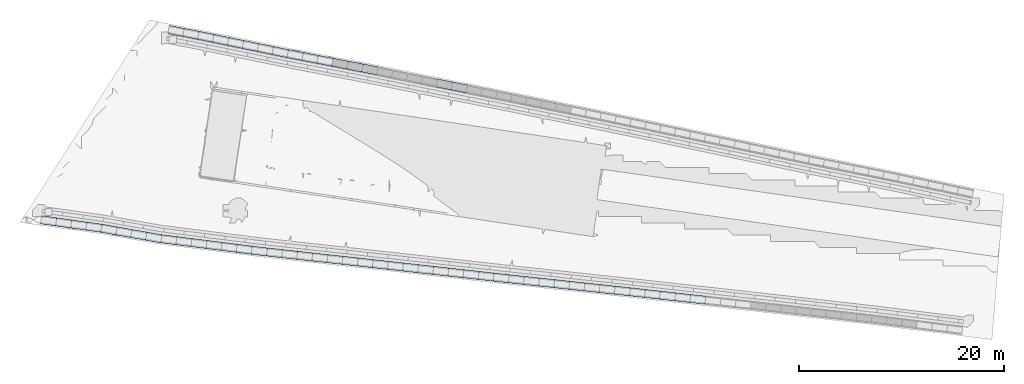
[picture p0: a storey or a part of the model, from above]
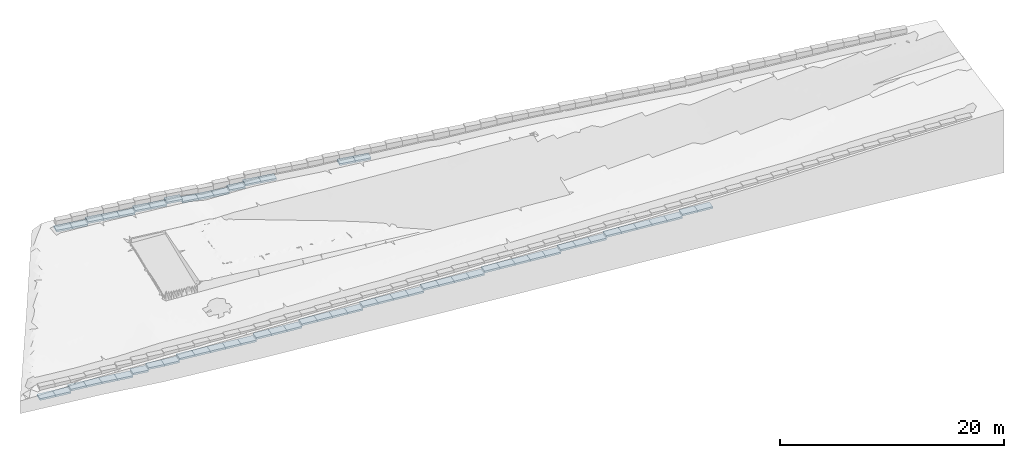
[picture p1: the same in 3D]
Properties of the parts of a building model (IFC4), part 1 of 3

# File
Description: ViewDefinition [CoordinationView]
File name: Casa_Sobreposta_Implantada.ifc
Time: 2026-10-02T10:00:33
Written by: IfcOpenShell 0.8.0
Made in: IfcOpenShell 0.8.0

# IfcProject, Casa Sobreposta · Lares · R05
Pset_CasaModel - Design: Casa Sobreposta; snapshot of current local configurator; ReferenceFile: 260617_CasaDFL_Estrutura_Terreno.ifc; ModelStatus: DESIGN_STUDY; North: Survey grid +Y; UpperFinishedFloor_m: 3.24; UpperDimensions: 32.00 x 7.90 m; Ramp: REMOVED R05; greenhouse via two existing internal stairs; EngineeringStatus: Member sizes, foundations, connections, bracing and environmental performance not verified; GroundFFL_m: 13.9; AreaLimit_m2: 250; CountedGeometricArea_m2: 248.622; GreenhouseExcludedByUser: yes

# IfcSite, Lares · Rua das Mercês · artigo 4771
Pset_SurveySource - File: GN_09.26_213 Lares.dwg; SHA256: 0bca0a0751148bad1398f92d81b795428f94a57fea5e37dec0e125cea70402a1; Area_m2: 1636.5; BoundaryHandle: 31B; CoordinateReference: PT-TM06 / ETRS89; TerrainStatus: Proposed grading; original survey in separate IFC

# IfcBuilding, Casa Sobreposta
Pset_CasaFloorAssembly - UpperFFL_m: 3.24; JoistUnderside_m: 2.968; JoistDepth_m: 0.24; OSB_m: 0.02; Membrane_m: 0.002; ProtectiveFinish_m: 0.01; Basis: TJI240 + OSB20 from reference; greenhouse waterproofing/finish assumed; imposed loads unverified
Pset_CasaPlacement - GroundFloorSurveyLevel_m: 13.9; GreenhouseSurveyLevel_m: 17.14; RotationFromGridEast_deg: -8.5; BoundarySetbackRequired_m: 3; RuleBasis: User project constraint

# IfcBuildingStorey (3)
In: Casa Sobreposta
Name | Elevation (m)
00 · Habitação e estacionamento | 13.9
01 · Jardim de inverno | 17.14
-01 · Cisterna sob o terraço | 11.3

# IfcSpace (18)
Pset_CasaProvenance - DesignSource: Casa Sobreposta / configuration.json; ReferenceFile: 260617_CasaDFL_Estrutura_Terreno.ifc; ConstructionBasis: DESIGN_ASSUMPTION; Note: Functional zone from configurator; overlaps with partition footprints removed on ground floor. Not certified usable floor area.
Name | In | PredefinedType | NetFloorArea (m2)
Sala | 00 · Habitação e estacionamento | INTERNAL | 31.359
Cozinha | 00 · Habitação e estacionamento | INTERNAL | 9.94248
Banho | 00 · Habitação e estacionamento | INTERNAL | 7.19804
WC | 00 · Habitação e estacionamento | INTERNAL | 1.231
Serviço | 00 · Habitação e estacionamento | INTERNAL | 4.16058
Acesso IS | 00 · Habitação e estacionamento | INTERNAL | 3.99017
Quarto 1 | 00 · Habitação e estacionamento | INTERNAL | 13.1145
Quarto 2 | 00 · Habitação e estacionamento | INTERNAL | 13.1145
Quarto / escritório | 00 · Habitação e estacionamento | INTERNAL | 37.8909
Circulação | 00 · Habitação e estacionamento | INTERNAL | 18.1139
Estacionamento · 2 lugares | 00 · Habitação e estacionamento | EXTERNAL | 32.55
Galeria sul · balanço 1,50 m | 01 · Jardim de inverno | INTERNAL | 48
Jardim de inverno | 01 · Jardim de inverno | INTERNAL | 47.852
Circulação / estar | 01 · Jardim de inverno | INTERNAL | 68.8278
Banho superior | 01 · Jardim de inverno | INTERNAL | 7.3678
Cultivo / jardim | 01 · Jardim de inverno | INTERNAL | 25.5734
Estar sobre a garagem | 01 · Jardim de inverno | INTERNAL | 21.292
Balanço | 01 · Jardim de inverno | INTERNAL | 25.6

# IfcAirToAirHeatRecovery, VMC com recuperação · esquema
In: 00 · Habitação e estacionamento
PredefinedType: FIXEDPLATECOUNTERFLOWEXCHANGER; Material: Aço galvanizado / Stahl verzinkt
Pset_CasaProvenance - DesignSource: Casa Sobreposta / configuration.json; ReferenceFile: 260617_CasaDFL_Estrutura_Terreno.ifc; ConstructionBasis: DESIGN_ASSUMPTION

# IfcAnnotation (4)
Pset_CasaProvenance - DesignSource: Casa Sobreposta / configuration.json; ReferenceFile: 260617_CasaDFL_Estrutura_Terreno.ifc; ConstructionBasis: DESIGN_ASSUMPTION
Name | In
Lugar P1 · 2.50 x 5.00 m | 00 · Habitação e estacionamento
Lugar P2 · 2.50 x 5.00 m | 00 · Habitação e estacionamento
Limite levantado · 31B | Lares · Rua das Mercês · artigo 4771
Afastamento de implantação · 3 m | Lares · Rua das Mercês · artigo 4771

# IfcBeam (104)
In: 01 · Jardim de inverno
Material: Madeira / Bauholz (2), OSB
Pset_CasaProvenance - DesignSource: Casa Sobreposta / configuration.json; ReferenceFile: 260617_CasaDFL_Estrutura_Terreno.ifc; ConstructionBasis: ADAPTED_REFERENCE; Note: Composite wood flanges + OSB web; 600 mm study spacing. Reference 44.45 mm width / 9.525 mm web; flanges regularised to 28 mm. Not structurally sized.
Name
TJI240 · 0.065 / -1.15
TJI240 · 4.065 / -1.15
TJI240 · 8.065 / -1.15
TJI240 · 12.065 / -1.15
TJI240 · 16.065 / -1.15
TJI240 · 20.065 / -1.15
TJI240 · 24.065 / -1.15
TJI240 · 28.065 / -1.15
TJI240 · 0.065 / -0.55
TJI240 · 4.065 / -0.55
TJI240 · 8.065 / -0.55
TJI240 · 12.065 / -0.55
TJI240 · 16.065 / -0.55
TJI240 · 20.065 / -0.55
TJI240 · 24.065 / -0.55
TJI240 · 28.065 / -0.55
TJI240 · 0.065 / 0.05
TJI240 · 4.065 / 0.05
TJI240 · 8.065 / 0.05
TJI240 · 12.065 / 0.05
TJI240 · 16.065 / 0.05
TJI240 · 20.065 / 0.05
TJI240 · 24.065 / 0.05
TJI240 · 28.065 / 0.05
TJI240 · 0.065 / 0.65
TJI240 · 4.065 / 0.65
TJI240 · 8.065 / 0.65
TJI240 · 12.065 / 0.65
TJI240 · 16.065 / 0.65
TJI240 · 20.065 / 0.65
TJI240 · 24.065 / 0.65
TJI240 · 28.065 / 0.65
TJI240 · 0.970 / 1.25
TJI240 · 4.065 / 1.25
TJI240 · 8.065 / 1.25
TJI240 · 12.065 / 1.25
TJI240 · 16.065 / 1.25
TJI240 · 20.065 / 1.25
TJI240 · 25.040 / 1.25
TJI240 · 28.065 / 1.25
TJI240 · 0.970 / 1.85
TJI240 · 4.065 / 1.85
TJI240 · 8.065 / 1.85
TJI240 · 12.065 / 1.85
TJI240 · 16.065 / 1.85
TJI240 · 20.065 / 1.85
TJI240 · 25.040 / 1.85
TJI240 · 28.065 / 1.85
TJI240 · 0.970 / 2.45
TJI240 · 4.065 / 2.45
TJI240 · 8.065 / 2.45
TJI240 · 12.065 / 2.45
TJI240 · 16.065 / 2.45
TJI240 · 20.065 / 2.45
TJI240 · 25.040 / 2.45
TJI240 · 28.065 / 2.45
TJI240 · 0.970 / 3.05
TJI240 · 4.065 / 3.05
TJI240 · 8.065 / 3.05
TJI240 · 12.065 / 3.05
TJI240 · 16.065 / 3.05
TJI240 · 20.065 / 3.05
TJI240 · 25.040 / 3.05
TJI240 · 28.065 / 3.05
TJI240 · 0.970 / 3.65
TJI240 · 4.065 / 3.65
TJI240 · 8.065 / 3.65
TJI240 · 12.065 / 3.65
TJI240 · 16.065 / 3.65
TJI240 · 20.065 / 3.65
TJI240 · 25.040 / 3.65
TJI240 · 28.065 / 3.65
TJI240 · 0.970 / 4.25
TJI240 · 4.065 / 4.25
TJI240 · 8.065 / 4.25
TJI240 · 12.065 / 4.25
TJI240 · 16.065 / 4.25
TJI240 · 20.065 / 4.25
TJI240 · 25.040 / 4.25
TJI240 · 28.065 / 4.25
TJI240 · 0.970 / 4.85
TJI240 · 4.065 / 4.85
TJI240 · 8.065 / 4.85
TJI240 · 12.065 / 4.85
TJI240 · 16.065 / 4.85
TJI240 · 20.065 / 4.85
TJI240 · 25.040 / 4.85
TJI240 · 28.065 / 4.85
TJI240 · 0.970 / 5.45
TJI240 · 4.065 / 5.45
TJI240 · 8.065 / 5.45
TJI240 · 12.065 / 5.45
TJI240 · 16.065 / 5.45
TJI240 · 20.065 / 5.45
TJI240 · 25.040 / 5.45
TJI240 · 28.065 / 5.45
TJI240 · 0.065 / 6.05
TJI240 · 4.065 / 6.05
TJI240 · 8.065 / 6.05
TJI240 · 12.065 / 6.05
TJI240 · 16.065 / 6.05
TJI240 · 20.065 / 6.05
TJI240 · 24.065 / 6.05
TJI240 · 28.065 / 6.05

# IfcBeam: IPE240 / steel (46)
Type - Material: Aço pintado / Stahl lackiert
Pset_CasaProvenance - DesignSource: Casa Sobreposta / configuration.json; ReferenceFile: 260617_CasaDFL_Estrutura_Terreno.ifc; ConstructionBasis: ADAPTED_REFERENCE; Note: Reference section; spans, stability and connections require design.
Name | In
Viga longitudinal 0 / 0.12 | 01 · Jardim de inverno
Viga longitudinal 4 / 0.12 | 01 · Jardim de inverno
Viga longitudinal 8 / 0.12 | 01 · Jardim de inverno
Viga longitudinal 12 / 0.12 | 01 · Jardim de inverno
Viga longitudinal 16 / 0.12 | 01 · Jardim de inverno
Viga longitudinal 20 / 0.12 | 01 · Jardim de inverno
Viga longitudinal 24 / 0.12 | 01 · Jardim de inverno
Viga longitudinal 28 / 0.12 | 01 · Jardim de inverno
Viga longitudinal 0 / 6.28 | 01 · Jardim de inverno
Viga longitudinal 4 / 6.28 | 01 · Jardim de inverno
Viga longitudinal 8 / 6.28 | 01 · Jardim de inverno
Viga longitudinal 12 / 6.28 | 01 · Jardim de inverno
Viga longitudinal 16 / 6.28 | 01 · Jardim de inverno
Viga longitudinal 20 / 6.28 | 01 · Jardim de inverno
Viga longitudinal 24 / 6.28 | 01 · Jardim de inverno
Viga longitudinal 28 / 6.28 | 01 · Jardim de inverno
Viga longitudinal 0 / -1.44 | 01 · Jardim de inverno
Viga longitudinal 4 / -1.44 | 01 · Jardim de inverno
Viga longitudinal 8 / -1.44 | 01 · Jardim de inverno
Viga longitudinal 12 / -1.44 | 01 · Jardim de inverno
Viga longitudinal 16 / -1.44 | 01 · Jardim de inverno
Viga longitudinal 20 / -1.44 | 01 · Jardim de inverno
Viga longitudinal 24 / -1.44 | 01 · Jardim de inverno
Viga longitudinal 28 / -1.44 | 01 · Jardim de inverno
2 x Viga transversal eixo 0 | 01 · Jardim de inverno
Viga transversal eixo 4 | 01 · Jardim de inverno
Viga transversal eixo 8 | 01 · Jardim de inverno
Viga transversal eixo 12 | 01 · Jardim de inverno
Viga transversal eixo 16 | 01 · Jardim de inverno
Viga transversal eixo 20 | 01 · Jardim de inverno
Viga transversal eixo 24 | 01 · Jardim de inverno
Viga transversal eixo 28 | 01 · Jardim de inverno
Viga transversal eixo 32 | 01 · Jardim de inverno
2 x Longarina do vão 1 | 01 · Jardim de inverno
2 x Cabeceira do vão 1 | 01 · Jardim de inverno
2 x Longarina do vão 2 | 01 · Jardim de inverno
2 x Cabeceira do vão 2 | 01 · Jardim de inverno
2 x Varanda · viga de bordo | 00 · Habitação e estacionamento
2 x Varanda · viga transversal | 00 · Habitação e estacionamento

# IfcBeam: RHS100x60x4 / steel (4)
In: 00 · Habitação e estacionamento
Type - Material: Aço pintado / Stahl lackiert
Pset_CasaProvenance - DesignSource: Casa Sobreposta / configuration.json; ReferenceFile: 260617_CasaDFL_Estrutura_Terreno.ifc; ConstructionBasis: DESIGN_ASSUMPTION; Note: Reference section; spans, stability and connections require design.

# IfcBuildingElementProxy: Cisterna · água a 2,00 m, hipótese
In: -01 · Cisterna sob o terraço
PredefinedType: USERDEFINED; Material: Água pluvial · nível ilustrativo
Pset_CasaProvenance - DesignSource: Casa Sobreposta / configuration.json; ReferenceFile: 260617_CasaDFL_Estrutura_Terreno.ifc; ConstructionBasis: DESIGN_ASSUMPTION; Note: Illustrative water envelope, not concrete or a certified operating capacity.

# IfcBuildingElementProxy: DRAINAGE_COLLECTION_RESERVE (2)
In: Lares · Rua das Mercês · artigo 4771
PredefinedType: USERDEFINED; Material: Betão armado / Stahlbeton
Pset_CasaProvenance - DesignSource: Casa Sobreposta / configuration.json; ReferenceFile: 260617_CasaDFL_Estrutura_Terreno.ifc; ConstructionBasis: DESIGN_ASSUMPTION; Note: Collection/silt chamber spatial reserve; outlet and storage not designed. No discharge to neighbour is assumed.
Name
Limite north · reserva de caixa de recolha
Limite south · reserva de caixa de recolha

# IfcBuildingElementProxy: INTERCEPTOR_SWALE (87)
In: Lares · Rua das Mercês · artigo 4771
PredefinedType: USERDEFINED; Material: Brita drenante
Pset_CasaProvenance - DesignSource: Casa Sobreposta / configuration.json; ReferenceFile: 260617_CasaDFL_Estrutura_Terreno.ifc; ConstructionBasis: DESIGN_ASSUMPTION; Note: Gravel-bottom interception swale; 0.90 m overall terrain cut, nominal 0.18 m depth. Filter, gradients, capacity and permitted outlet require hydraulic design.
Name
Limite north · vala drenante 01
Limite north · vala drenante 02
Limite north · vala drenante 03
Limite north · vala drenante 04
Limite north · vala drenante 05
Limite north · vala drenante 06
Limite north · vala drenante 07
Limite north · vala drenante 08
Limite north · vala drenante 09
Limite north · vala drenante 10
Limite north · vala drenante 11
Limite north · vala drenante 12
Limite north · vala drenante 13
Limite north · vala drenante 14
Limite north · vala drenante 15
Limite north · vala drenante 16
Limite north · vala drenante 17
Limite north · vala drenante 18
Limite north · vala drenante 19
Limite north · vala drenante 20
Limite north · vala drenante 21
Limite north · vala drenante 22
Limite north · vala drenante 23
Limite north · vala drenante 24
Limite north · vala drenante 25
Limite north · vala drenante 26
Limite north · vala drenante 27
Limite north · vala drenante 28
Limite north · vala drenante 29
Limite north · vala drenante 30
Limite north · vala drenante 31
Limite north · vala drenante 32
Limite north · vala drenante 33
Limite north · vala drenante 34
Limite north · vala drenante 35
Limite north · vala drenante 36
Limite north · vala drenante 37
Limite north · vala drenante 38
Limite north · vala drenante 39
Limite north · vala drenante 40
Limite north · vala drenante 41
Limite south · vala drenante 01
Limite south · vala drenante 02
Limite south · vala drenante 03
Limite south · vala drenante 04
Limite south · vala drenante 05
Limite south · vala drenante 06
Limite south · vala drenante 07
Limite south · vala drenante 08
Limite south · vala drenante 09
Limite south · vala drenante 10
Limite south · vala drenante 11
Limite south · vala drenante 12
Limite south · vala drenante 13
Limite south · vala drenante 14
Limite south · vala drenante 15
Limite south · vala drenante 16
Limite south · vala drenante 17
Limite south · vala drenante 18
Limite south · vala drenante 19
Limite south · vala drenante 20
Limite south · vala drenante 21
Limite south · vala drenante 22
Limite south · vala drenante 23
Limite south · vala drenante 24
Limite south · vala drenante 25
Limite south · vala drenante 26
Limite south · vala drenante 27
Limite south · vala drenante 28
Limite south · vala drenante 29
Limite south · vala drenante 30
Limite south · vala drenante 31
Limite south · vala drenante 32
Limite south · vala drenante 33
Limite south · vala drenante 34
Limite south · vala drenante 35
Limite south · vala drenante 36
Limite south · vala drenante 37
Limite south · vala drenante 38
Limite south · vala drenante 39
Limite south · vala drenante 40
Limite south · vala drenante 41
Limite south · vala drenante 42
Limite south · vala drenante 43
Limite south · vala drenante 44
Limite south · vala drenante 45
Limite south · vala drenante 46

# IfcBuildingElementProxy: Trepadeiras · floreira (10)
In: 00 · Habitação e estacionamento
PredefinedType: USERDEFINED; Material: Betão armado / Stahlbeton
Pset_CasaProvenance - DesignSource: Casa Sobreposta / configuration.json; ReferenceFile: 260617_CasaDFL_Estrutura_Terreno.ifc; ConstructionBasis: DESIGN_ASSUMPTION; Note: Indicative planter; soil volume, irrigation, root space and waterproofing to design.

# IfcColumn (16)
In: 00 · Habitação e estacionamento
Material: Betão armado / Stahlbeton
Pset_CasaProvenance - DesignSource: Casa Sobreposta / configuration.json; ReferenceFile: 260617_CasaDFL_Estrutura_Terreno.ifc; ConstructionBasis: ADAPTED_REFERENCE
Name
Pedestal 1A · betão 400 x 400
Pedestal 1B · betão 400 x 400
Pedestal 2A · betão 400 x 400
Pedestal 2B · betão 400 x 400
Pedestal 3A · betão 400 x 400
Pedestal 3B · betão 400 x 400
Pedestal 4A · betão 400 x 400
Pedestal 4B · betão 400 x 400
Pedestal 5A · betão 400 x 400
Pedestal 5B · betão 400 x 400
Pedestal 6A · betão 400 x 400
Pedestal 6B · betão 400 x 400
Pedestal 7A · betão 400 x 400
Pedestal 7B · betão 400 x 400
Pedestal 8A · betão 400 x 400
Pedestal 8B · betão 400 x 400

# IfcColumn: IPE240 / steel (46)
Type - Material: Aço pintado / Stahl lackiert
Pset_CasaProvenance - DesignSource: Casa Sobreposta / configuration.json; ReferenceFile: 260617_CasaDFL_Estrutura_Terreno.ifc; ConstructionBasis: ADAPTED_REFERENCE; Note: Reference section; spans, stability and connections require design.
Name | In
Pilar 1A · IPE240 | 00 · Habitação e estacionamento
Pilar estufa 1A · IPE240 | 01 · Jardim de inverno
Pilar 1B · IPE240 | 00 · Habitação e estacionamento
Pilar estufa 1B · IPE240 | 01 · Jardim de inverno
Pilar 2A · IPE240 | 00 · Habitação e estacionamento
Pilar estufa 2A · IPE240 | 01 · Jardim de inverno
Pilar 2B · IPE240 | 00 · Habitação e estacionamento
Pilar estufa 2B · IPE240 | 01 · Jardim de inverno
Pilar 3A · IPE240 | 00 · Habitação e estacionamento
Pilar estufa 3A · IPE240 | 01 · Jardim de inverno
Pilar 3B · IPE240 | 00 · Habitação e estacionamento
Pilar estufa 3B · IPE240 | 01 · Jardim de inverno
Pilar 4A · IPE240 | 00 · Habitação e estacionamento
Pilar estufa 4A · IPE240 | 01 · Jardim de inverno
Pilar 4B · IPE240 | 00 · Habitação e estacionamento
Pilar estufa 4B · IPE240 | 01 · Jardim de inverno
Pilar 5A · IPE240 | 00 · Habitação e estacionamento
Pilar estufa 5A · IPE240 | 01 · Jardim de inverno
Pilar 5B · IPE240 | 00 · Habitação e estacionamento
Pilar estufa 5B · IPE240 | 01 · Jardim de inverno
Pilar 6A · IPE240 | 00 · Habitação e estacionamento
Pilar estufa 6A · IPE240 | 01 · Jardim de inverno
Pilar 6B · IPE240 | 00 · Habitação e estacionamento
Pilar estufa 6B · IPE240 | 01 · Jardim de inverno
Pilar 7A · IPE240 | 00 · Habitação e estacionamento
Pilar estufa 7A · IPE240 | 01 · Jardim de inverno
Pilar 7B · IPE240 | 00 · Habitação e estacionamento
Pilar estufa 7B · IPE240 | 01 · Jardim de inverno
Pilar 8A · IPE240 | 00 · Habitação e estacionamento
Pilar estufa 8A · IPE240 | 01 · Jardim de inverno
Pilar 8B · IPE240 | 00 · Habitação e estacionamento
Pilar estufa 8B · IPE240 | 01 · Jardim de inverno
4 x Pérgola · pilar de duplo pé-direito | 00 · Habitação e estacionamento
9 x Projeção estufa · pilar sul ao pódio | 00 · Habitação e estacionamento
Projeção estufa · pilar nascente norte | 00 · Habitação e estacionamento

# IfcColumn: RHS80x60x4 / steel (4)
In: 00 · Habitação e estacionamento
Type - Material: Aço pintado / Stahl lackiert
Pset_CasaProvenance - DesignSource: Casa Sobreposta / configuration.json; ReferenceFile: 260617_CasaDFL_Estrutura_Terreno.ifc; ConstructionBasis: DESIGN_ASSUMPTION; Note: Reference section; spans, stability and connections require design.

# IfcCovering (9)
Pset_CasaProvenance - DesignSource: Casa Sobreposta / configuration.json; ReferenceFile: 260617_CasaDFL_Estrutura_Terreno.ifc; ConstructionBasis: DESIGN_ASSUMPTION
Name | In | PredefinedType | Material
Impermeabilização da estufa · hipótese | 01 · Jardim de inverno | FLOORING | Membrana impermeável — hipótese | Pset_CasaProvenance - Note: Two real stair voids. Light protective finish assumed; drains and waterproof upstands require detailing.
Proteção do pavimento · hipótese | 01 · Jardim de inverno | FLOORING | Pavimento protetor leve — hipótese | Pset_CasaProvenance - Note: Two real stair voids. Light protective finish assumed; drains and waterproof upstands require detailing.
Teto caixa térmica 1 | 01 · Jardim de inverno | CEILING | Pavimento protetor leve — hipótese
Teto caixa térmica 2 | 01 · Jardim de inverno | CEILING | Pavimento protetor leve — hipótese
Cisterna · camada drenante 100 mm | -01 · Cisterna sob o terraço | FLOORING | Brita drenante
Cisterna · impermeabilização poente | -01 · Cisterna sob o terraço | MEMBRANE | Membrana impermeável — hipótese
Cisterna · impermeabilização norte | -01 · Cisterna sob o terraço | MEMBRANE | Membrana impermeável — hipótese
Cisterna · impermeabilização sul | -01 · Cisterna sob o terraço | MEMBRANE | Membrana impermeável — hipótese
Cisterna · impermeabilização nascente | -01 · Cisterna sob o terraço | MEMBRANE | Membrana impermeável — hipótese

# IfcCovering: Cortina interior · 75% (9)
In: 01 · Jardim de inverno
PredefinedType: USERDEFINED; Material: Tecido de sombreamento — hipótese
Pset_CasaProvenance - DesignSource: Casa Sobreposta / configuration.json; ReferenceFile: 260617_CasaDFL_Estrutura_Terreno.ifc; ConstructionBasis: DESIGN_ASSUMPTION; Note: 75% deployment snapshot; fabric specification and cables not sized.

# IfcCovering: Pátio · sombreador têxtil retrátil (2)
In: 00 · Habitação e estacionamento
PredefinedType: USERDEFINED; Material: Tecido de sombreamento — hipótese
Pset_CasaProvenance - DesignSource: Casa Sobreposta / configuration.json; ReferenceFile: 260617_CasaDFL_Estrutura_Terreno.ifc; ConstructionBasis: DESIGN_ASSUMPTION; Note: Same fabric intent as internal shades, shown partially deployed. No wind-speed rating; retraction does not prove storm safety.

# IfcDistributionSystem (7)
Name | PredefinedType
cold · traçados preliminares | DOMESTICCOLDWATER
hot · traçados preliminares | DOMESTICHOTWATER
waste · traçados preliminares | DRAINAGE
vent · traçados preliminares | VENT
supply · traçados preliminares | VENTILATION
extract · traçados preliminares | VENTILATION
ground · traçados preliminares | HEATING

# IfcDoor (22)
PredefinedType: DOOR
Pset_CasaProvenance - DesignSource: Casa Sobreposta / configuration.json; ReferenceFile: 260617_CasaDFL_Estrutura_Terreno.ifc
Name | In | OverallHeight (m) | OverallWidth (m) | OperationType | Material | ConstructionBasis
Porta interior 1 | 00 · Habitação e estacionamento | 2.1 | 0.830093 | SINGLE_SWING_LEFT | OSB | ADAPTED_REFERENCE
Porta interior 2 | 00 · Habitação e estacionamento | 2.1 | 0.830093 | SINGLE_SWING_LEFT | OSB | ADAPTED_REFERENCE
Porta interior 3 | 00 · Habitação e estacionamento | 2.1 | 0.730086 | SINGLE_SWING_LEFT | OSB | ADAPTED_REFERENCE
Porta interior 4 | 00 · Habitação e estacionamento | 2.1 | 0.830092 | SINGLE_SWING_LEFT | OSB | ADAPTED_REFERENCE
Porta interior 5 | 00 · Habitação e estacionamento | 2.1 | 0.830077 | SINGLE_SWING_LEFT | OSB | ADAPTED_REFERENCE
Porta interior 6 | 00 · Habitação e estacionamento | 2.1 | 0.730017 | SINGLE_SWING_LEFT | OSB | ADAPTED_REFERENCE
Porta do estacionamento | 00 · Habitação e estacionamento | 2.1 | 0.83 | SINGLE_SWING_LEFT | Aço pintado / Stahl lackiert | ADAPTED_REFERENCE
Folha de correr sul 2 | 00 · Habitação e estacionamento | 2.918 | 1.97133 | SLIDING_TO_LEFT | Vidro / Normalglas | DESIGN_ASSUMPTION
Folha de correr sul 4 | 00 · Habitação e estacionamento | 2.918 | 1.97133 | SLIDING_TO_LEFT | Vidro / Normalglas | DESIGN_ASSUMPTION
Folha de correr sul 6 | 00 · Habitação e estacionamento | 2.918 | 1.97133 | SLIDING_TO_LEFT | Vidro / Normalglas | DESIGN_ASSUMPTION
Folha de correr sul 8 | 00 · Habitação e estacionamento | 2.918 | 1.97133 | SLIDING_TO_LEFT | Vidro / Normalglas | DESIGN_ASSUMPTION
Folha de correr sul 10 | 00 · Habitação e estacionamento | 2.918 | 1.97133 | SLIDING_TO_LEFT | Vidro / Normalglas | DESIGN_ASSUMPTION
Folha de correr sul 12 | 00 · Habitação e estacionamento | 2.918 | 0.614 | SLIDING_TO_LEFT | Vidro / Normalglas | DESIGN_ASSUMPTION
Fachada poente integralmente envidraçada · módulo 4 | 00 · Habitação e estacionamento | 2.918 | 1.55 | SLIDING_TO_LEFT | Vidro / Normalglas | DESIGN_ASSUMPTION | Pset_CasaGlazedFacade - Revision: R02 · kiwi pergola; Facade: WEST / highlighted end in user sketch; Infill: Full-height glazing; no opaque infill; GlazingSpecification: 8 mm nominal representation only; insulated safety glazing assembly to specify
Porta banho superior | 01 · Jardim de inverno | 2.1 | 0.8 | SINGLE_SWING_LEFT | OSB | ADAPTED_REFERENCE
Varanda · porta de correr oeste | 01 · Jardim de inverno | 2.15 | 1.05 | SLIDING_TO_LEFT | Vidro / Normalglas | DESIGN_ASSUMPTION
Caixa térmica 1 · north | 01 · Jardim de inverno | 2.15 | 0.9 | SLIDING_TO_LEFT | Vidro / Normalglas | DESIGN_ASSUMPTION
Caixa térmica 2 · south | 01 · Jardim de inverno | 2.15 | 0.91 | SLIDING_TO_LEFT | Vidro / Normalglas | DESIGN_ASSUMPTION
2 x Contentor · porta dupla | 00 · Habitação e estacionamento | 2.39 | 1.17 | SINGLE_SWING_LEFT | Contentor · pintura 1 | DESIGN_ASSUMPTION
2 x Contentor · porta dupla | 00 · Habitação e estacionamento | 2.39 | 1.17 | SINGLE_SWING_LEFT | Contentor · pintura 2 | DESIGN_ASSUMPTION

# IfcDuctSegment: D0.09 / extract (8)
In: 00 · Habitação e estacionamento
Type - Material: extract · traçado de estudo
Pset_CasaProvenance - DesignSource: Casa Sobreposta / configuration.json; ReferenceFile: 260617_CasaDFL_Estrutura_Terreno.ifc; ConstructionBasis: DESIGN_ASSUMPTION; Note: Route only. Display diameter is not a specified pipe/duct size; fittings, ports, insulation and sizing not developed.
Group: extract · traçados preliminares

# IfcDuctSegment: D0.09 / supply (11)
In: 00 · Habitação e estacionamento
Type - Material: supply · traçado de estudo
Pset_CasaProvenance - DesignSource: Casa Sobreposta / configuration.json; ReferenceFile: 260617_CasaDFL_Estrutura_Terreno.ifc; ConstructionBasis: DESIGN_ASSUMPTION; Note: Route only. Display diameter is not a specified pipe/duct size; fittings, ports, insulation and sizing not developed.
Group: supply · traçados preliminares

# IfcElementAssembly: CISTERN_PODIUM, Pódio · projeção da estufa e cisterna
In: 00 · Habitação e estacionamento
PredefinedType: USERDEFINED
Pset_CasaProvenance - DesignSource: Casa Sobreposta / configuration.json; ReferenceFile: 260617_CasaDFL_Estrutura_Terreno.ifc; ConstructionBasis: DESIGN_ASSUMPTION
Pset_CasaPodium - TankGrossPlan_m2: 23; TankBaseLevel_m: 11.3; MinimumInternalHeight_m: 2.31; FloorSupport: Suspended west terrace; east platform on engineered fill; PlanningAssumption: 23 m2 still reserved conservatively in counted schedule; no tank exemption asserted

# IfcElementAssembly: EXISTING_SHIPPING_CONTAINER (2)
In: 00 · Habitação e estacionamento
PredefinedType: USERDEFINED
Pset_CasaProvenance - DesignSource: Casa Sobreposta / configuration.json; ReferenceFile: 260617_CasaDFL_Estrutura_Terreno.ifc; ConstructionBasis: DESIGN_ASSUMPTION
Pset_CasaExistingContext - Length_m: 6; WidthAssumed_m: 2.44; HeightAssumed_m: 2.59; Location: Approximate from user plan markup, not surveyed; Status: Existing context; not included in new building setback or new floor-area schedule; Colour: Illustrative, condition not surveyed
Name
Contentor existente 1 · 6 m
Contentor existente 2 · 6 m

# IfcElementAssembly: LIVING_SHADE_TRELLIS, Fachada sul e pátio · estrutura e trepadeiras
In: 00 · Habitação e estacionamento
PredefinedType: USERDEFINED
Pset_CasaProvenance - DesignSource: Casa Sobreposta / configuration.json; ReferenceFile: 260617_CasaDFL_Estrutura_Terreno.ifc; ConstructionBasis: DESIGN_ASSUMPTION

# IfcElementAssembly: PERGOLA_GREENHOUSE_EXTENSION, Pérgola · prolongamento da estufa 6 m
In: 00 · Habitação e estacionamento
PredefinedType: USERDEFINED
Pset_CasaProvenance - DesignSource: Casa Sobreposta / configuration.json; ReferenceFile: 260617_CasaDFL_Estrutura_Terreno.ifc; ConstructionBasis: DESIGN_ASSUMPTION
Pset_CasaVeranda - ClearWidth_m: 1.2; GrossArea_m2: 9.875; PlanningStatus: Counted conservatively in 250 m2 budget; municipal classification unconfirmed
Pset_CasaPergola - Projection_m: 6; Frontage_m: 7.9; OpenCanopyArea_m2: 47.4; EavesRelativeHeight_m: 6.22; Roof: Open extension of greenhouse curved profile, no glass enclosure; StructuralStatus: Gravity and lateral load path indicated; no wind-speed rating or member/anchor verification

# IfcFooting (179)
Material: Betão armado / Stahlbeton
Pset_CasaProvenance - DesignSource: Casa Sobreposta / configuration.json; ReferenceFile: 260617_CasaDFL_Estrutura_Terreno.ifc
Name | In | PredefinedType | ConstructionBasis | Note
Sapata 1A · hipótese | 00 · Habitação e estacionamento | PAD_FOOTING | ADAPTED_REFERENCE | 1.20 x 1.20 x 0.35 m assumed pad; R03 steps below original ground where survey is available. Bearing, settlement and reinforcement unverified.
Sapata 1B · hipótese | 00 · Habitação e estacionamento | PAD_FOOTING | ADAPTED_REFERENCE | 1.20 x 1.20 x 0.35 m assumed pad; R03 steps below original ground where survey is available. Bearing, settlement and reinforcement unverified.
Sapata 2A · hipótese | 00 · Habitação e estacionamento | PAD_FOOTING | ADAPTED_REFERENCE | 1.20 x 1.20 x 0.35 m assumed pad; R03 steps below original ground where survey is available. Bearing, settlement and reinforcement unverified.
Sapata 2B · hipótese | 00 · Habitação e estacionamento | PAD_FOOTING | ADAPTED_REFERENCE | 1.20 x 1.20 x 0.35 m assumed pad; R03 steps below original ground where survey is available. Bearing, settlement and reinforcement unverified.
Sapata 3A · hipótese | 00 · Habitação e estacionamento | PAD_FOOTING | ADAPTED_REFERENCE | 1.20 x 1.20 x 0.35 m assumed pad; R03 steps below original ground where survey is available. Bearing, settlement and reinforcement unverified.
Sapata 3B · hipótese | 00 · Habitação e estacionamento | PAD_FOOTING | ADAPTED_REFERENCE | 1.20 x 1.20 x 0.35 m assumed pad; R03 steps below original ground where survey is available. Bearing, settlement and reinforcement unverified.
Sapata 4A · hipótese | 00 · Habitação e estacionamento | PAD_FOOTING | ADAPTED_REFERENCE | 1.20 x 1.20 x 0.35 m assumed pad; R03 steps below original ground where survey is available. Bearing, settlement and reinforcement unverified.
Sapata 4B · hipótese | 00 · Habitação e estacionamento | PAD_FOOTING | ADAPTED_REFERENCE | 1.20 x 1.20 x 0.35 m assumed pad; R03 steps below original ground where survey is available. Bearing, settlement and reinforcement unverified.
Sapata 5A · hipótese | 00 · Habitação e estacionamento | PAD_FOOTING | ADAPTED_REFERENCE | 1.20 x 1.20 x 0.35 m assumed pad; R03 steps below original ground where survey is available. Bearing, settlement and reinforcement unverified.
Sapata 5B · hipótese | 00 · Habitação e estacionamento | PAD_FOOTING | ADAPTED_REFERENCE | 1.20 x 1.20 x 0.35 m assumed pad; R03 steps below original ground where survey is available. Bearing, settlement and reinforcement unverified.
Sapata 6A · hipótese | 00 · Habitação e estacionamento | PAD_FOOTING | ADAPTED_REFERENCE | 1.20 x 1.20 x 0.35 m assumed pad; R03 steps below original ground where survey is available. Bearing, settlement and reinforcement unverified.
Sapata 6B · hipótese | 00 · Habitação e estacionamento | PAD_FOOTING | ADAPTED_REFERENCE | 1.20 x 1.20 x 0.35 m assumed pad; R03 steps below original ground where survey is available. Bearing, settlement and reinforcement unverified.
Sapata 7A · hipótese | 00 · Habitação e estacionamento | PAD_FOOTING | ADAPTED_REFERENCE | 1.20 x 1.20 x 0.35 m assumed pad; R03 steps below original ground where survey is available. Bearing, settlement and reinforcement unverified.
Sapata 7B · hipótese | 00 · Habitação e estacionamento | PAD_FOOTING | ADAPTED_REFERENCE | 1.20 x 1.20 x 0.35 m assumed pad; R03 steps below original ground where survey is available. Bearing, settlement and reinforcement unverified.
Sapata 8A · hipótese | 00 · Habitação e estacionamento | PAD_FOOTING | ADAPTED_REFERENCE | 1.20 x 1.20 x 0.35 m assumed pad; R03 steps below original ground where survey is available. Bearing, settlement and reinforcement unverified.
Sapata 8B · hipótese | 00 · Habitação e estacionamento | PAD_FOOTING | ADAPTED_REFERENCE | 1.20 x 1.20 x 0.35 m assumed pad; R03 steps below original ground where survey is available. Bearing, settlement and reinforcement unverified.
Cisterna · sapata corrida poente | -01 · Cisterna sob o terraço | STRIP_FOOTING | DESIGN_ASSUMPTION
Cisterna · sapata corrida norte | -01 · Cisterna sob o terraço | STRIP_FOOTING | DESIGN_ASSUMPTION
Cisterna · sapata corrida sul | -01 · Cisterna sob o terraço | STRIP_FOOTING | DESIGN_ASSUMPTION
Cisterna · sapata corrida nascente | -01 · Cisterna sob o terraço | STRIP_FOOTING | DESIGN_ASSUMPTION
4 x Jardim · apoio | 00 · Habitação e estacionamento | PAD_FOOTING | DESIGN_ASSUMPTION
16 x Pódio · fundação sul | 00 · Habitação e estacionamento | STRIP_FOOTING | DESIGN_ASSUMPTION
16 x Pódio · fundação norte | 00 · Habitação e estacionamento | STRIP_FOOTING | DESIGN_ASSUMPTION
8 x Contentor · apoio existente indicativo | 00 · Habitação e estacionamento | PAD_FOOTING | DESIGN_ASSUMPTION
Limite north · base 01 | Lares · Rua das Mercês · artigo 4771 | STRIP_FOOTING | DESIGN_ASSUMPTION | Nominal 800 x 200 mm bed; indicative only. All work within parcel, separate from building setback.
Limite north · base 02 | Lares · Rua das Mercês · artigo 4771 | STRIP_FOOTING | DESIGN_ASSUMPTION | Nominal 800 x 200 mm bed; indicative only. All work within parcel, separate from building setback.
Limite north · base 03 | Lares · Rua das Mercês · artigo 4771 | STRIP_FOOTING | DESIGN_ASSUMPTION | Nominal 800 x 200 mm bed; indicative only. All work within parcel, separate from building setback.
Limite north · base 04 | Lares · Rua das Mercês · artigo 4771 | STRIP_FOOTING | DESIGN_ASSUMPTION | Nominal 800 x 200 mm bed; indicative only. All work within parcel, separate from building setback.
Limite north · base 05 | Lares · Rua das Mercês · artigo 4771 | STRIP_FOOTING | DESIGN_ASSUMPTION | Nominal 800 x 200 mm bed; indicative only. All work within parcel, separate from building setback.
Limite north · base 06 | Lares · Rua das Mercês · artigo 4771 | STRIP_FOOTING | DESIGN_ASSUMPTION | Nominal 800 x 200 mm bed; indicative only. All work within parcel, separate from building setback.
Limite north · base 07 | Lares · Rua das Mercês · artigo 4771 | STRIP_FOOTING | DESIGN_ASSUMPTION | Nominal 800 x 200 mm bed; indicative only. All work within parcel, separate from building setback.
Limite north · base 08 | Lares · Rua das Mercês · artigo 4771 | STRIP_FOOTING | DESIGN_ASSUMPTION | Nominal 800 x 200 mm bed; indicative only. All work within parcel, separate from building setback.
Limite north · base 09 | Lares · Rua das Mercês · artigo 4771 | STRIP_FOOTING | DESIGN_ASSUMPTION | Nominal 800 x 200 mm bed; indicative only. All work within parcel, separate from building setback.
Limite north · base 10 | Lares · Rua das Mercês · artigo 4771 | STRIP_FOOTING | DESIGN_ASSUMPTION | Nominal 800 x 200 mm bed; indicative only. All work within parcel, separate from building setback.
Limite north · base 11 | Lares · Rua das Mercês · artigo 4771 | STRIP_FOOTING | DESIGN_ASSUMPTION | Nominal 800 x 200 mm bed; indicative only. All work within parcel, separate from building setback.
Limite north · base 12 | Lares · Rua das Mercês · artigo 4771 | STRIP_FOOTING | DESIGN_ASSUMPTION | Nominal 800 x 200 mm bed; indicative only. All work within parcel, separate from building setback.
Limite north · base 13 | Lares · Rua das Mercês · artigo 4771 | STRIP_FOOTING | DESIGN_ASSUMPTION | Nominal 800 x 200 mm bed; indicative only. All work within parcel, separate from building setback.
Limite north · base 14 | Lares · Rua das Mercês · artigo 4771 | STRIP_FOOTING | DESIGN_ASSUMPTION | Nominal 800 x 200 mm bed; indicative only. All work within parcel, separate from building setback.
Limite north · base 15 | Lares · Rua das Mercês · artigo 4771 | STRIP_FOOTING | DESIGN_ASSUMPTION | Nominal 800 x 200 mm bed; indicative only. All work within parcel, separate from building setback.
Limite north · base 16 | Lares · Rua das Mercês · artigo 4771 | STRIP_FOOTING | DESIGN_ASSUMPTION | Nominal 800 x 200 mm bed; indicative only. All work within parcel, separate from building setback.
Limite north · base 17 | Lares · Rua das Mercês · artigo 4771 | STRIP_FOOTING | DESIGN_ASSUMPTION | Nominal 800 x 200 mm bed; indicative only. All work within parcel, separate from building setback.
Limite north · base 18 | Lares · Rua das Mercês · artigo 4771 | STRIP_FOOTING | DESIGN_ASSUMPTION | Nominal 800 x 200 mm bed; indicative only. All work within parcel, separate from building setback.
Limite north · base 19 | Lares · Rua das Mercês · artigo 4771 | STRIP_FOOTING | DESIGN_ASSUMPTION | Nominal 800 x 200 mm bed; indicative only. All work within parcel, separate from building setback.
Limite north · base 20 | Lares · Rua das Mercês · artigo 4771 | STRIP_FOOTING | DESIGN_ASSUMPTION | Nominal 800 x 200 mm bed; indicative only. All work within parcel, separate from building setback.
Limite north · base 21 | Lares · Rua das Mercês · artigo 4771 | STRIP_FOOTING | DESIGN_ASSUMPTION | Nominal 800 x 200 mm bed; indicative only. All work within parcel, separate from building setback.
Limite north · base 22 | Lares · Rua das Mercês · artigo 4771 | STRIP_FOOTING | DESIGN_ASSUMPTION | Nominal 800 x 200 mm bed; indicative only. All work within parcel, separate from building setback.
Limite north · base 23 | Lares · Rua das Mercês · artigo 4771 | STRIP_FOOTING | DESIGN_ASSUMPTION | Nominal 800 x 200 mm bed; indicative only. All work within parcel, separate from building setback.
Limite north · base 24 | Lares · Rua das Mercês · artigo 4771 | STRIP_FOOTING | DESIGN_ASSUMPTION | Nominal 800 x 200 mm bed; indicative only. All work within parcel, separate from building setback.
Limite north · base 25 | Lares · Rua das Mercês · artigo 4771 | STRIP_FOOTING | DESIGN_ASSUMPTION | Nominal 800 x 200 mm bed; indicative only. All work within parcel, separate from building setback.
Limite north · base 26 | Lares · Rua das Mercês · artigo 4771 | STRIP_FOOTING | DESIGN_ASSUMPTION | Nominal 800 x 200 mm bed; indicative only. All work within parcel, separate from building setback.
Limite north · base 27 | Lares · Rua das Mercês · artigo 4771 | STRIP_FOOTING | DESIGN_ASSUMPTION | Nominal 800 x 200 mm bed; indicative only. All work within parcel, separate from building setback.
Limite north · base 28 | Lares · Rua das Mercês · artigo 4771 | STRIP_FOOTING | DESIGN_ASSUMPTION | Nominal 800 x 200 mm bed; indicative only. All work within parcel, separate from building setback.
Limite north · base 29 | Lares · Rua das Mercês · artigo 4771 | STRIP_FOOTING | DESIGN_ASSUMPTION | Nominal 800 x 200 mm bed; indicative only. All work within parcel, separate from building setback.
Limite north · base 30 | Lares · Rua das Mercês · artigo 4771 | STRIP_FOOTING | DESIGN_ASSUMPTION | Nominal 800 x 200 mm bed; indicative only. All work within parcel, separate from building setback.
Limite north · base 31 | Lares · Rua das Mercês · artigo 4771 | STRIP_FOOTING | DESIGN_ASSUMPTION | Nominal 800 x 200 mm bed; indicative only. All work within parcel, separate from building setback.
Limite north · base 32 | Lares · Rua das Mercês · artigo 4771 | STRIP_FOOTING | DESIGN_ASSUMPTION | Nominal 800 x 200 mm bed; indicative only. All work within parcel, separate from building setback.
Limite north · base 33 | Lares · Rua das Mercês · artigo 4771 | STRIP_FOOTING | DESIGN_ASSUMPTION | Nominal 800 x 200 mm bed; indicative only. All work within parcel, separate from building setback.
Limite north · base 34 | Lares · Rua das Mercês · artigo 4771 | STRIP_FOOTING | DESIGN_ASSUMPTION | Nominal 800 x 200 mm bed; indicative only. All work within parcel, separate from building setback.
Limite north · base 35 | Lares · Rua das Mercês · artigo 4771 | STRIP_FOOTING | DESIGN_ASSUMPTION | Nominal 800 x 200 mm bed; indicative only. All work within parcel, separate from building setback.
Limite north · base 36 | Lares · Rua das Mercês · artigo 4771 | STRIP_FOOTING | DESIGN_ASSUMPTION | Nominal 800 x 200 mm bed; indicative only. All work within parcel, separate from building setback.
Limite north · base 37 | Lares · Rua das Mercês · artigo 4771 | STRIP_FOOTING | DESIGN_ASSUMPTION | Nominal 800 x 200 mm bed; indicative only. All work within parcel, separate from building setback.
Limite north · base 38 | Lares · Rua das Mercês · artigo 4771 | STRIP_FOOTING | DESIGN_ASSUMPTION | Nominal 800 x 200 mm bed; indicative only. All work within parcel, separate from building setback.
Limite north · base 39 | Lares · Rua das Mercês · artigo 4771 | STRIP_FOOTING | DESIGN_ASSUMPTION | Nominal 800 x 200 mm bed; indicative only. All work within parcel, separate from building setback.
Limite north · base 40 | Lares · Rua das Mercês · artigo 4771 | STRIP_FOOTING | DESIGN_ASSUMPTION | Nominal 800 x 200 mm bed; indicative only. All work within parcel, separate from building setback.
Limite north · base 41 | Lares · Rua das Mercês · artigo 4771 | STRIP_FOOTING | DESIGN_ASSUMPTION | Nominal 800 x 200 mm bed; indicative only. All work within parcel, separate from building setback.
Limite north · base 42 | Lares · Rua das Mercês · artigo 4771 | STRIP_FOOTING | DESIGN_ASSUMPTION | Nominal 800 x 200 mm bed; indicative only. All work within parcel, separate from building setback.
Limite north · base 43 | Lares · Rua das Mercês · artigo 4771 | STRIP_FOOTING | DESIGN_ASSUMPTION | Nominal 800 x 200 mm bed; indicative only. All work within parcel, separate from building setback.
Limite north · base 44 | Lares · Rua das Mercês · artigo 4771 | STRIP_FOOTING | DESIGN_ASSUMPTION | Nominal 800 x 200 mm bed; indicative only. All work within parcel, separate from building setback.
Limite north · base 45 | Lares · Rua das Mercês · artigo 4771 | STRIP_FOOTING | DESIGN_ASSUMPTION | Nominal 800 x 200 mm bed; indicative only. All work within parcel, separate from building setback.
Limite north · base 46 | Lares · Rua das Mercês · artigo 4771 | STRIP_FOOTING | DESIGN_ASSUMPTION | Nominal 800 x 200 mm bed; indicative only. All work within parcel, separate from building setback.
Limite north · base 47 | Lares · Rua das Mercês · artigo 4771 | STRIP_FOOTING | DESIGN_ASSUMPTION | Nominal 800 x 200 mm bed; indicative only. All work within parcel, separate from building setback.
Limite north · base 48 | Lares · Rua das Mercês · artigo 4771 | STRIP_FOOTING | DESIGN_ASSUMPTION | Nominal 800 x 200 mm bed; indicative only. All work within parcel, separate from building setback.
Limite north · base 49 | Lares · Rua das Mercês · artigo 4771 | STRIP_FOOTING | DESIGN_ASSUMPTION | Nominal 800 x 200 mm bed; indicative only. All work within parcel, separate from building setback.
Limite north · base 50 | Lares · Rua das Mercês · artigo 4771 | STRIP_FOOTING | DESIGN_ASSUMPTION | Nominal 800 x 200 mm bed; indicative only. All work within parcel, separate from building setback.
Limite north · base 51 | Lares · Rua das Mercês · artigo 4771 | STRIP_FOOTING | DESIGN_ASSUMPTION | Nominal 800 x 200 mm bed; indicative only. All work within parcel, separate from building setback.
Limite north · base 52 | Lares · Rua das Mercês · artigo 4771 | STRIP_FOOTING | DESIGN_ASSUMPTION | Nominal 800 x 200 mm bed; indicative only. All work within parcel, separate from building setback.
Limite north · base 53 | Lares · Rua das Mercês · artigo 4771 | STRIP_FOOTING | DESIGN_ASSUMPTION | Nominal 800 x 200 mm bed; indicative only. All work within parcel, separate from building setback.
Limite north · base 54 | Lares · Rua das Mercês · artigo 4771 | STRIP_FOOTING | DESIGN_ASSUMPTION | Nominal 800 x 200 mm bed; indicative only. All work within parcel, separate from building setback.
Limite south · base 01 | Lares · Rua das Mercês · artigo 4771 | STRIP_FOOTING | DESIGN_ASSUMPTION | Nominal 800 x 200 mm bed; indicative only. All work within parcel, separate from building setback.
Limite south · base 02 | Lares · Rua das Mercês · artigo 4771 | STRIP_FOOTING | DESIGN_ASSUMPTION | Nominal 800 x 200 mm bed; indicative only. All work within parcel, separate from building setback.
Limite south · base 03 | Lares · Rua das Mercês · artigo 4771 | STRIP_FOOTING | DESIGN_ASSUMPTION | Nominal 800 x 200 mm bed; indicative only. All work within parcel, separate from building setback.
Limite south · base 04 | Lares · Rua das Mercês · artigo 4771 | STRIP_FOOTING | DESIGN_ASSUMPTION | Nominal 800 x 200 mm bed; indicative only. All work within parcel, separate from building setback.
Limite south · base 05 | Lares · Rua das Mercês · artigo 4771 | STRIP_FOOTING | DESIGN_ASSUMPTION | Nominal 800 x 200 mm bed; indicative only. All work within parcel, separate from building setback.
Limite south · base 06 | Lares · Rua das Mercês · artigo 4771 | STRIP_FOOTING | DESIGN_ASSUMPTION | Nominal 800 x 200 mm bed; indicative only. All work within parcel, separate from building setback.
Limite south · base 07 | Lares · Rua das Mercês · artigo 4771 | STRIP_FOOTING | DESIGN_ASSUMPTION | Nominal 800 x 200 mm bed; indicative only. All work within parcel, separate from building setback.
Limite south · base 08 | Lares · Rua das Mercês · artigo 4771 | STRIP_FOOTING | DESIGN_ASSUMPTION | Nominal 800 x 200 mm bed; indicative only. All work within parcel, separate from building setback.
Limite south · base 09 | Lares · Rua das Mercês · artigo 4771 | STRIP_FOOTING | DESIGN_ASSUMPTION | Nominal 800 x 200 mm bed; indicative only. All work within parcel, separate from building setback.
Limite south · base 10 | Lares · Rua das Mercês · artigo 4771 | STRIP_FOOTING | DESIGN_ASSUMPTION | Nominal 800 x 200 mm bed; indicative only. All work within parcel, separate from building setback.
Limite south · base 11 | Lares · Rua das Mercês · artigo 4771 | STRIP_FOOTING | DESIGN_ASSUMPTION | Nominal 800 x 200 mm bed; indicative only. All work within parcel, separate from building setback.
Limite south · base 12 | Lares · Rua das Mercês · artigo 4771 | STRIP_FOOTING | DESIGN_ASSUMPTION | Nominal 800 x 200 mm bed; indicative only. All work within parcel, separate from building setback.
Limite south · base 13 | Lares · Rua das Mercês · artigo 4771 | STRIP_FOOTING | DESIGN_ASSUMPTION | Nominal 800 x 200 mm bed; indicative only. All work within parcel, separate from building setback.
Limite south · base 14 | Lares · Rua das Mercês · artigo 4771 | STRIP_FOOTING | DESIGN_ASSUMPTION | Nominal 800 x 200 mm bed; indicative only. All work within parcel, separate from building setback.
Limite south · base 15 | Lares · Rua das Mercês · artigo 4771 | STRIP_FOOTING | DESIGN_ASSUMPTION | Nominal 800 x 200 mm bed; indicative only. All work within parcel, separate from building setback.
Limite south · base 16 | Lares · Rua das Mercês · artigo 4771 | STRIP_FOOTING | DESIGN_ASSUMPTION | Nominal 800 x 200 mm bed; indicative only. All work within parcel, separate from building setback.
Limite south · base 17 | Lares · Rua das Mercês · artigo 4771 | STRIP_FOOTING | DESIGN_ASSUMPTION | Nominal 800 x 200 mm bed; indicative only. All work within parcel, separate from building setback.
Limite south · base 18 | Lares · Rua das Mercês · artigo 4771 | STRIP_FOOTING | DESIGN_ASSUMPTION | Nominal 800 x 200 mm bed; indicative only. All work within parcel, separate from building setback.
Limite south · base 19 | Lares · Rua das Mercês · artigo 4771 | STRIP_FOOTING | DESIGN_ASSUMPTION | Nominal 800 x 200 mm bed; indicative only. All work within parcel, separate from building setback.
Limite south · base 20 | Lares · Rua das Mercês · artigo 4771 | STRIP_FOOTING | DESIGN_ASSUMPTION | Nominal 800 x 200 mm bed; indicative only. All work within parcel, separate from building setback.
Limite south · base 21 | Lares · Rua das Mercês · artigo 4771 | STRIP_FOOTING | DESIGN_ASSUMPTION | Nominal 800 x 200 mm bed; indicative only. All work within parcel, separate from building setback.
Limite south · base 22 | Lares · Rua das Mercês · artigo 4771 | STRIP_FOOTING | DESIGN_ASSUMPTION | Nominal 800 x 200 mm bed; indicative only. All work within parcel, separate from building setback.
Limite south · base 23 | Lares · Rua das Mercês · artigo 4771 | STRIP_FOOTING | DESIGN_ASSUMPTION | Nominal 800 x 200 mm bed; indicative only. All work within parcel, separate from building setback.
Limite south · base 24 | Lares · Rua das Mercês · artigo 4771 | STRIP_FOOTING | DESIGN_ASSUMPTION | Nominal 800 x 200 mm bed; indicative only. All work within parcel, separate from building setback.
Limite south · base 25 | Lares · Rua das Mercês · artigo 4771 | STRIP_FOOTING | DESIGN_ASSUMPTION | Nominal 800 x 200 mm bed; indicative only. All work within parcel, separate from building setback.
Limite south · base 26 | Lares · Rua das Mercês · artigo 4771 | STRIP_FOOTING | DESIGN_ASSUMPTION | Nominal 800 x 200 mm bed; indicative only. All work within parcel, separate from building setback.
Limite south · base 27 | Lares · Rua das Mercês · artigo 4771 | STRIP_FOOTING | DESIGN_ASSUMPTION | Nominal 800 x 200 mm bed; indicative only. All work within parcel, separate from building setback.
Limite south · base 28 | Lares · Rua das Mercês · artigo 4771 | STRIP_FOOTING | DESIGN_ASSUMPTION | Nominal 800 x 200 mm bed; indicative only. All work within parcel, separate from building setback.
Limite south · base 29 | Lares · Rua das Mercês · artigo 4771 | STRIP_FOOTING | DESIGN_ASSUMPTION | Nominal 800 x 200 mm bed; indicative only. All work within parcel, separate from building setback.
Limite south · base 30 | Lares · Rua das Mercês · artigo 4771 | STRIP_FOOTING | DESIGN_ASSUMPTION | Nominal 800 x 200 mm bed; indicative only. All work within parcel, separate from building setback.
Limite south · base 31 | Lares · Rua das Mercês · artigo 4771 | STRIP_FOOTING | DESIGN_ASSUMPTION | Nominal 800 x 200 mm bed; indicative only. All work within parcel, separate from building setback.
Limite south · base 32 | Lares · Rua das Mercês · artigo 4771 | STRIP_FOOTING | DESIGN_ASSUMPTION | Nominal 800 x 200 mm bed; indicative only. All work within parcel, separate from building setback.
Limite south · base 33 | Lares · Rua das Mercês · artigo 4771 | STRIP_FOOTING | DESIGN_ASSUMPTION | Nominal 800 x 200 mm bed; indicative only. All work within parcel, separate from building setback.
Limite south · base 34 | Lares · Rua das Mercês · artigo 4771 | STRIP_FOOTING | DESIGN_ASSUMPTION | Nominal 800 x 200 mm bed; indicative only. All work within parcel, separate from building setback.
Limite south · base 35 | Lares · Rua das Mercês · artigo 4771 | STRIP_FOOTING | DESIGN_ASSUMPTION | Nominal 800 x 200 mm bed; indicative only. All work within parcel, separate from building setback.
Limite south · base 36 | Lares · Rua das Mercês · artigo 4771 | STRIP_FOOTING | DESIGN_ASSUMPTION | Nominal 800 x 200 mm bed; indicative only. All work within parcel, separate from building setback.
Limite south · base 37 | Lares · Rua das Mercês · artigo 4771 | STRIP_FOOTING | DESIGN_ASSUMPTION | Nominal 800 x 200 mm bed; indicative only. All work within parcel, separate from building setback.
Limite south · base 38 | Lares · Rua das Mercês · artigo 4771 | STRIP_FOOTING | DESIGN_ASSUMPTION | Nominal 800 x 200 mm bed; indicative only. All work within parcel, separate from building setback.
Limite south · base 39 | Lares · Rua das Mercês · artigo 4771 | STRIP_FOOTING | DESIGN_ASSUMPTION | Nominal 800 x 200 mm bed; indicative only. All work within parcel, separate from building setback.
Limite south · base 40 | Lares · Rua das Mercês · artigo 4771 | STRIP_FOOTING | DESIGN_ASSUMPTION | Nominal 800 x 200 mm bed; indicative only. All work within parcel, separate from building setback.
Limite south · base 41 | Lares · Rua das Mercês · artigo 4771 | STRIP_FOOTING | DESIGN_ASSUMPTION | Nominal 800 x 200 mm bed; indicative only. All work within parcel, separate from building setback.
Limite south · base 42 | Lares · Rua das Mercês · artigo 4771 | STRIP_FOOTING | DESIGN_ASSUMPTION | Nominal 800 x 200 mm bed; indicative only. All work within parcel, separate from building setback.
Limite south · base 43 | Lares · Rua das Mercês · artigo 4771 | STRIP_FOOTING | DESIGN_ASSUMPTION | Nominal 800 x 200 mm bed; indicative only. All work within parcel, separate from building setback.
Limite south · base 44 | Lares · Rua das Mercês · artigo 4771 | STRIP_FOOTING | DESIGN_ASSUMPTION | Nominal 800 x 200 mm bed; indicative only. All work within parcel, separate from building setback.
Limite south · base 45 | Lares · Rua das Mercês · artigo 4771 | STRIP_FOOTING | DESIGN_ASSUMPTION | Nominal 800 x 200 mm bed; indicative only. All work within parcel, separate from building setback.
Limite south · base 46 | Lares · Rua das Mercês · artigo 4771 | STRIP_FOOTING | DESIGN_ASSUMPTION | Nominal 800 x 200 mm bed; indicative only. All work within parcel, separate from building setback.
Limite south · base 47 | Lares · Rua das Mercês · artigo 4771 | STRIP_FOOTING | DESIGN_ASSUMPTION | Nominal 800 x 200 mm bed; indicative only. All work within parcel, separate from building setback.
Limite south · base 48 | Lares · Rua das Mercês · artigo 4771 | STRIP_FOOTING | DESIGN_ASSUMPTION | Nominal 800 x 200 mm bed; indicative only. All work within parcel, separate from building setback.
Limite south · base 49 | Lares · Rua das Mercês · artigo 4771 | STRIP_FOOTING | DESIGN_ASSUMPTION | Nominal 800 x 200 mm bed; indicative only. All work within parcel, separate from building setback.
Limite south · base 50 | Lares · Rua das Mercês · artigo 4771 | STRIP_FOOTING | DESIGN_ASSUMPTION | Nominal 800 x 200 mm bed; indicative only. All work within parcel, separate from building setback.
Limite south · base 51 | Lares · Rua das Mercês · artigo 4771 | STRIP_FOOTING | DESIGN_ASSUMPTION | Nominal 800 x 200 mm bed; indicative only. All work within parcel, separate from building setback.
Limite south · base 52 | Lares · Rua das Mercês · artigo 4771 | STRIP_FOOTING | DESIGN_ASSUMPTION | Nominal 800 x 200 mm bed; indicative only. All work within parcel, separate from building setback.
Limite south · base 53 | Lares · Rua das Mercês · artigo 4771 | STRIP_FOOTING | DESIGN_ASSUMPTION | Nominal 800 x 200 mm bed; indicative only. All work within parcel, separate from building setback.
Limite south · base 54 | Lares · Rua das Mercês · artigo 4771 | STRIP_FOOTING | DESIGN_ASSUMPTION | Nominal 800 x 200 mm bed; indicative only. All work within parcel, separate from building setback.
Limite south · base 55 | Lares · Rua das Mercês · artigo 4771 | STRIP_FOOTING | DESIGN_ASSUMPTION | Nominal 800 x 200 mm bed; indicative only. All work within parcel, separate from building setback.
Limite south · base 56 | Lares · Rua das Mercês · artigo 4771 | STRIP_FOOTING | DESIGN_ASSUMPTION | Nominal 800 x 200 mm bed; indicative only. All work within parcel, separate from building setback.
Limite south · base 57 | Lares · Rua das Mercês · artigo 4771 | STRIP_FOOTING | DESIGN_ASSUMPTION | Nominal 800 x 200 mm bed; indicative only. All work within parcel, separate from building setback.
Limite south · base 58 | Lares · Rua das Mercês · artigo 4771 | STRIP_FOOTING | DESIGN_ASSUMPTION | Nominal 800 x 200 mm bed; indicative only. All work within parcel, separate from building setback.
Limite south · base 59 | Lares · Rua das Mercês · artigo 4771 | STRIP_FOOTING | DESIGN_ASSUMPTION | Nominal 800 x 200 mm bed; indicative only. All work within parcel, separate from building setback.
Limite south · base 60 | Lares · Rua das Mercês · artigo 4771 | STRIP_FOOTING | DESIGN_ASSUMPTION | Nominal 800 x 200 mm bed; indicative only. All work within parcel, separate from building setback.
Limite south · base 61 | Lares · Rua das Mercês · artigo 4771 | STRIP_FOOTING | DESIGN_ASSUMPTION | Nominal 800 x 200 mm bed; indicative only. All work within parcel, separate from building setback.

# IfcFurnishingElement, Ilha da cozinha · esquema
In: 00 · Habitação e estacionamento
Material: OSB
Pset_CasaProvenance - DesignSource: Casa Sobreposta / configuration.json; ReferenceFile: 260617_CasaDFL_Estrutura_Terreno.ifc; ConstructionBasis: ADAPTED_REFERENCE

# IfcGeographicElement, Terreno · R05 com escavação dos cisterna
In: Lares · Rua das Mercês · artigo 4771
PredefinedType: TERRAIN; Material: Terreno · modelação proposta
Pset_CasaProvenance - DesignSource: Casa Sobreposta / configuration.json; ReferenceFile: 260617_CasaDFL_Estrutura_Terreno.ifc; ConstructionBasis: DESIGN_ASSUMPTION

# IfcGeographicElement: ANALYTICAL_CUT_VOLUME, Escavação · diferença entre terrenos
In: Lares · Rua das Mercês · artigo 4771
PredefinedType: USERDEFINED; Material: Escavação · volume analítico
Pset_CasaProvenance - DesignSource: Casa Sobreposta / configuration.json; ReferenceFile: 260617_CasaDFL_Estrutura_Terreno.ifc; ConstructionBasis: DESIGN_ASSUMPTION; Note: ANALYTICAL VOLUME, not additional constructed material. Closed wedges between surveyed and proposed TIN, split where sign changes. Excludes stripping, foundations, services and bulking.
Pset_CasaEarthworks - Kind: CUT; Volume_m3: 192.468; Method: Exact signed integration of linear proposed/existing display TIN, splitting zero crossings; Excluded: Topsoil stripping, foundation/service trenches, soil replacement, bulking and shrinkage; Status: CONCEPT_GEOMETRIC_VOLUME; not a measured bill of works; DefaultVisibility: Hide analytical volumes in normal model views
Qto_CasaEarthworks - NetVolume: 192.468 m3

# IfcGeographicElement: ANALYTICAL_FILL_VOLUME, Aterro · diferença entre terrenos
In: Lares · Rua das Mercês · artigo 4771
PredefinedType: USERDEFINED; Material: Aterro · volume analítico
Pset_CasaProvenance - DesignSource: Casa Sobreposta / configuration.json; ReferenceFile: 260617_CasaDFL_Estrutura_Terreno.ifc; ConstructionBasis: DESIGN_ASSUMPTION; Note: ANALYTICAL VOLUME, not additional constructed material. Closed wedges between surveyed and proposed TIN, split where sign changes. Excludes stripping, foundations, services and bulking.
Pset_CasaEarthworks - Kind: FILL; Volume_m3: 39.7831; Method: Exact signed integration of linear proposed/existing display TIN, splitting zero crossings; Excluded: Topsoil stripping, foundation/service trenches, soil replacement, bulking and shrinkage; Status: CONCEPT_GEOMETRIC_VOLUME; not a measured bill of works; DefaultVisibility: Hide analytical volumes in normal model views
Qto_CasaEarthworks - NetVolume: 39.7831 m3

# IfcGeographicElement: Acesso ao estacionamento · terreno
In: Lares · Rua das Mercês · artigo 4771
PredefinedType: USERDEFINED; Material: Acesso térreo
Pset_CasaProvenance - DesignSource: Casa Sobreposta / configuration.json; ReferenceFile: 260617_CasaDFL_Estrutura_Terreno.ifc; ConstructionBasis: DESIGN_ASSUMPTION

# IfcGeographicElement: VEGETATION, Trepadeiras · folhas individuais, estado ilustrativo
In: 00 · Habitação e estacionamento
PredefinedType: USERDEFINED; Material: Folhagem · trepadeiras
Pset_CasaProvenance - DesignSource: Casa Sobreposta / configuration.json; ReferenceFile: 260617_CasaDFL_Estrutura_Terreno.ifc; ConstructionBasis: DESIGN_ASSUMPTION; Note: Procedural leaves for visual intent only; no predicted growth, species performance or wind protection.

# IfcMember (154)
In: 00 · Habitação e estacionamento
Pset_CasaProvenance - DesignSource: Casa Sobreposta / configuration.json; ReferenceFile: 260617_CasaDFL_Estrutura_Terreno.ifc; ConstructionBasis: DESIGN_ASSUMPTION
Name | Material
4 x Contentor · canto | Contentor · pintura 1
50 x Contentor · nervura lateral | Contentor · pintura 1
23 x Contentor · nervura cobertura | Contentor · pintura 1
4 x Contentor · canto | Contentor · pintura 2
50 x Contentor · nervura lateral | Contentor · pintura 2
23 x Contentor · nervura cobertura | Contentor · pintura 2

# IfcMember: C240 / steel (6)
In: 00 · Habitação e estacionamento
Type - Material: Aço pintado / Stahl lackiert
Pset_CasaProvenance - DesignSource: Casa Sobreposta / configuration.json; ReferenceFile: 260617_CasaDFL_Estrutura_Terreno.ifc; ConstructionBasis: ADAPTED_REFERENCE; Note: Reference section; spans, stability and connections require design.
Name
2 x Longarina metálica sala
2 x Longarina metálica garagem
2 x Jardim · longarina

# IfcMember: D0.004 / galvanized (257)
In: 00 · Habitação e estacionamento
Type - Material: Aço galvanizado / Stahl verzinkt
Pset_CasaProvenance - DesignSource: Casa Sobreposta / configuration.json; ReferenceFile: 260617_CasaDFL_Estrutura_Terreno.ifc; ConstructionBasis: DESIGN_ASSUMPTION; Note: Reference section; spans, stability and connections require design.
Name
120 x Pérgola · fio para trepadeiras
70 x Trepadeiras · fio horizontal
67 x Trepadeiras · fio vertical

# IfcMember: D0.015 / vine_wood (627)
In: 00 · Habitação e estacionamento
Type - Material: Ramos de trepadeiras
Pset_CasaProvenance - DesignSource: Casa Sobreposta / configuration.json; ReferenceFile: 260617_CasaDFL_Estrutura_Terreno.ifc; ConstructionBasis: DESIGN_ASSUMPTION; Note: Reference section; spans, stability and connections require design.

# IfcMember: D0.016 / steel (2)
In: 00 · Habitação e estacionamento
Type - Material: Aço pintado / Stahl lackiert
Pset_CasaProvenance - DesignSource: Casa Sobreposta / configuration.json; ReferenceFile: 260617_CasaDFL_Estrutura_Terreno.ifc; ConstructionBasis: DESIGN_ASSUMPTION; Note: Reference section; spans, stability and connections require design.

# IfcMember: D0.025 / galvanized (8)
In: 00 · Habitação e estacionamento
Type - Material: Aço galvanizado / Stahl verzinkt
Pset_CasaProvenance - DesignSource: Casa Sobreposta / configuration.json; ReferenceFile: 260617_CasaDFL_Estrutura_Terreno.ifc; ConstructionBasis: DESIGN_ASSUMPTION; Note: Reference section; spans, stability and connections require design.

# IfcMember: R0.035 / steel (557)
Type - Material: Aço pintado / Stahl lackiert
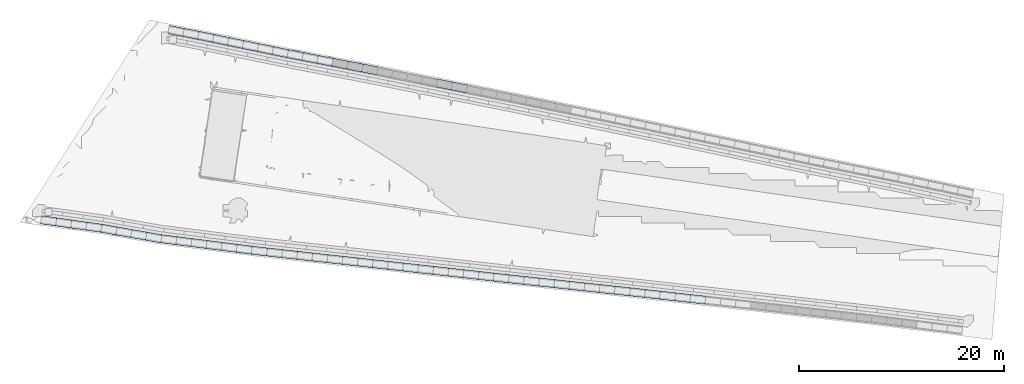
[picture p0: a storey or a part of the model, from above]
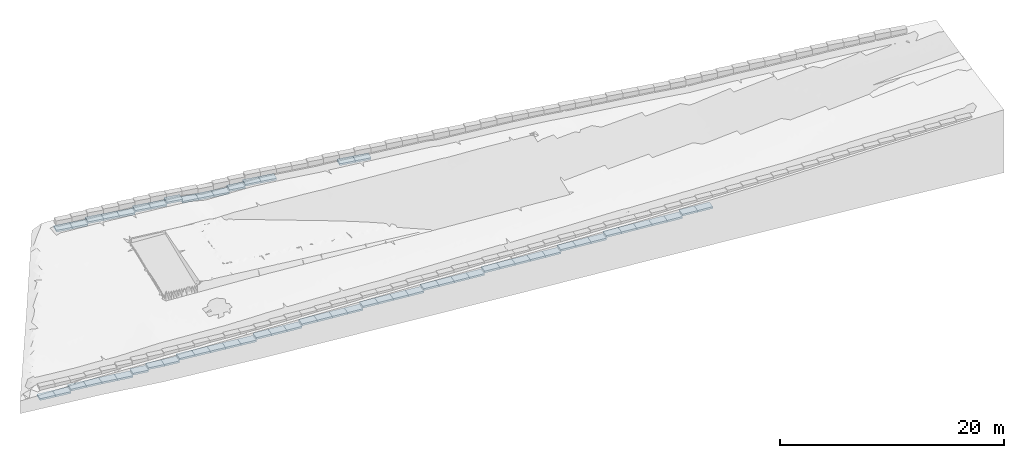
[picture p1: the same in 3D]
Properties of the parts of a building model (IFC4), part 3 of 3

# IfcWall: CONCEPT_STONE_RETAINING_EDGE (115)
Name | Side | NeighbourLevelRelativeToExistingOwnGround_m | TopSurveyLevel_m | BaseSurveyLevel_m
Limite south · pedra 42 | south | -0.5 | 14 | 12.75
Limite south · pedra 43 | south | -0.5 | 14.1 | 13
Limite south · pedra 44 | south | -0.5 | 14.2 | 13
Limite south · pedra 45 | south | -0.5 | 14.2 | 13
Limite south · pedra 46 | south | -0.5 | 14.3 | 13.25
Limite south · pedra 47 | south | -0.5 | 14.4 | 13.25
Limite south · pedra 48 | south | -0.5 | 14.5 | 13.25
Limite south · pedra 49 | south | -0.5 | 14.6 | 13.5
Limite south · pedra 50 | south | -0.5 | 14.7 | 13.5
Limite south · pedra 51 | south | -0.5 | 14.8 | 13.5
Limite south · pedra 52 | south | -0.5 | 14.9 | 13.75
Limite south · pedra 53 | south | -0.5 | 15 | 13.75
Limite south · pedra 54 | south | -0.5 | 15.1 | 14
Limite south · pedra 55 | south | -0.5 | 15.2 | 14
Limite south · pedra 56 | south | -0.5 | 15.3 | 14.25
Limite south · pedra 57 | south | -0.5 | 15.4 | 14.25
Limite south · pedra 58 | south | -0.5 | 15.5 | 14.25
Limite south · pedra 59 | south | -0.5 | 15.6 | 14.5
Limite south · pedra 60 | south | -0.5 | 15.7 | 14.5
Limite south · pedra 61 | south | -0.5 | 15.8 | 14.75

# IfcWall: Cisterna · parede nascente
In: -01 · Cisterna sob o terraço
PredefinedType: USERDEFINED; Material: Betão armado / Stahlbeton
Pset_CasaProvenance - DesignSource: Casa Sobreposta / configuration.json; ReferenceFile: 260617_CasaDFL_Estrutura_Terreno.ifc; ConstructionBasis: DESIGN_ASSUMPTION; Note: 250 mm RC study wall, waterproofing and joints to detail; no retaining capacity asserted.

# IfcWall: Cisterna · parede norte
In: -01 · Cisterna sob o terraço
PredefinedType: USERDEFINED; Material: Betão armado / Stahlbeton
Pset_CasaProvenance - DesignSource: Casa Sobreposta / configuration.json; ReferenceFile: 260617_CasaDFL_Estrutura_Terreno.ifc; ConstructionBasis: DESIGN_ASSUMPTION; Note: 250 mm RC study wall, waterproofing and joints to detail; no retaining capacity asserted.

# IfcWall: Cisterna · parede poente
In: -01 · Cisterna sob o terraço
PredefinedType: USERDEFINED; Material: Betão armado / Stahlbeton
Pset_CasaProvenance - DesignSource: Casa Sobreposta / configuration.json; ReferenceFile: 260617_CasaDFL_Estrutura_Terreno.ifc; ConstructionBasis: DESIGN_ASSUMPTION; Note: 250 mm RC study wall, waterproofing and joints to detail; no retaining capacity asserted.

# IfcWall: Cisterna · parede sul
In: -01 · Cisterna sob o terraço
PredefinedType: USERDEFINED; Material: Betão armado / Stahlbeton
Pset_CasaProvenance - DesignSource: Casa Sobreposta / configuration.json; ReferenceFile: 260617_CasaDFL_Estrutura_Terreno.ifc; ConstructionBasis: DESIGN_ASSUMPTION; Note: 250 mm RC study wall, waterproofing and joints to detail; no retaining capacity asserted.

# IfcWall: Pódio · bordo junto à cisterna (3)
In: 00 · Habitação e estacionamento
PredefinedType: USERDEFINED; Material: Betão armado / Stahlbeton
Pset_CasaProvenance - DesignSource: Casa Sobreposta / configuration.json; ReferenceFile: 260617_CasaDFL_Estrutura_Terreno.ifc; ConstructionBasis: DESIGN_ASSUMPTION

# IfcWall: Pódio · contenção norte (16)
In: 00 · Habitação e estacionamento
PredefinedType: USERDEFINED; Material: Betão armado / Stahlbeton
Pset_CasaProvenance - DesignSource: Casa Sobreposta / configuration.json; ReferenceFile: 260617_CasaDFL_Estrutura_Terreno.ifc; ConstructionBasis: DESIGN_ASSUMPTION

# IfcWall: Pódio · contenção sul (16)
In: 00 · Habitação e estacionamento
PredefinedType: USERDEFINED; Material: Betão armado / Stahlbeton
Pset_CasaProvenance - DesignSource: Casa Sobreposta / configuration.json; ReferenceFile: 260617_CasaDFL_Estrutura_Terreno.ifc; ConstructionBasis: DESIGN_ASSUMPTION

# IfcWindow (58)
PredefinedType: WINDOW; PartitioningType: SINGLE_PANEL; Material: Vidro / Normalglas
Pset_CasaProvenance - DesignSource: Casa Sobreposta / configuration.json; ReferenceFile: 260617_CasaDFL_Estrutura_Terreno.ifc; ConstructionBasis: DESIGN_ASSUMPTION
Name | In | OverallHeight (m) | OverallWidth (m)
Rasgo norte 1 | 00 · Habitação e estacionamento | 0.3 | 3.79
Rasgo norte 2 | 00 · Habitação e estacionamento | 0.3 | 3.79
Rasgo norte 3 | 00 · Habitação e estacionamento | 0.3 | 3.79
Rasgo norte 4 | 00 · Habitação e estacionamento | 0.3 | 3.79
Rasgo norte 5 | 00 · Habitação e estacionamento | 0.3 | 3.79
Rasgo norte 6 | 00 · Habitação e estacionamento | 0.3 | 3.79
Rasgo norte 7 | 00 · Habitação e estacionamento | 0.3 | 0.71
Fachada poente integralmente envidraçada · módulo 1 | 00 · Habitação e estacionamento | 2.918 | 1.55 | Pset_CasaGlazedFacade - Revision: R02 · kiwi pergola; Facade: WEST / highlighted end in user sketch; Infill: Full-height glazing; no opaque infill; GlazingSpecification: 8 mm nominal representation only; insulated safety glazing assembly to specify
Fachada poente integralmente envidraçada · módulo 2 | 00 · Habitação e estacionamento | 2.918 | 1.55 | Pset_CasaGlazedFacade - Revision: R02 · kiwi pergola; Facade: WEST / highlighted end in user sketch; Infill: Full-height glazing; no opaque infill; GlazingSpecification: 8 mm nominal representation only; insulated safety glazing assembly to specify
Fachada poente integralmente envidraçada · módulo 3 | 00 · Habitação e estacionamento | 2.918 | 1.55 | Pset_CasaGlazedFacade - Revision: R02 · kiwi pergola; Facade: WEST / highlighted end in user sketch; Infill: Full-height glazing; no opaque infill; GlazingSpecification: 8 mm nominal representation only; insulated safety glazing assembly to specify
Estufa sul 1 | 01 · Jardim de inverno | 2.43 | 1.95
Estufa sul 2 | 01 · Jardim de inverno | 2.43 | 1.95
Estufa sul 3 | 01 · Jardim de inverno | 2.43 | 1.95
Estufa sul 4 | 01 · Jardim de inverno | 2.43 | 1.95
Estufa sul 5 | 01 · Jardim de inverno | 2.43 | 1.95
Estufa sul 6 | 01 · Jardim de inverno | 2.43 | 1.95
Estufa sul 7 | 01 · Jardim de inverno | 2.43 | 1.95
Estufa sul 8 | 01 · Jardim de inverno | 2.43 | 1.95
Estufa sul 9 | 01 · Jardim de inverno | 2.43 | 1.95
Estufa sul 10 | 01 · Jardim de inverno | 2.43 | 1.95
Estufa sul 11 | 01 · Jardim de inverno | 2.43 | 1.95
Estufa sul 12 | 01 · Jardim de inverno | 2.43 | 1.95
Estufa sul 13 | 01 · Jardim de inverno | 2.43 | 1.95
Estufa sul 14 | 01 · Jardim de inverno | 2.43 | 1.95
Estufa sul 15 | 01 · Jardim de inverno | 2.43 | 1.95
Estufa sul 16 | 01 · Jardim de inverno | 2.43 | 1.95
Estufa norte 1 | 01 · Jardim de inverno | 2.43 | 1.95
Estufa norte 2 | 01 · Jardim de inverno | 2.43 | 1.95
Estufa norte 3 | 01 · Jardim de inverno | 2.43 | 1.95
Estufa norte 4 | 01 · Jardim de inverno | 2.43 | 1.95
Estufa norte 5 | 01 · Jardim de inverno | 2.43 | 1.95
Estufa norte 6 | 01 · Jardim de inverno | 2.43 | 1.95
Estufa norte 7 | 01 · Jardim de inverno | 2.43 | 1.95
Estufa norte 8 | 01 · Jardim de inverno | 2.43 | 1.95
Estufa norte 9 | 01 · Jardim de inverno | 2.43 | 1.95
Estufa norte 10 | 01 · Jardim de inverno | 2.43 | 1.95
Estufa norte 11 | 01 · Jardim de inverno | 2.43 | 1.95
Estufa norte 12 | 01 · Jardim de inverno | 2.43 | 1.95
Estufa norte 13 | 01 · Jardim de inverno | 2.43 | 1.95
Estufa norte 14 | 01 · Jardim de inverno | 2.43 | 1.95
Estufa norte 15 | 01 · Jardim de inverno | 2.43 | 1.95
Estufa norte 16 | 01 · Jardim de inverno | 2.43 | 1.95
Varanda · bandeira da porta | 01 · Jardim de inverno | 0.73 | 1.05
Varanda · vidro lateral | 01 · Jardim de inverno | 2.93 | 0.1
Varanda · vidro lateral | 01 · Jardim de inverno | 2.93 | 0.675
Estufa poente 2 | 01 · Jardim de inverno | 2.93 | 1.925
Estufa poente 3 | 01 · Jardim de inverno | 2.93 | 1.925
Estufa poente 4 | 01 · Jardim de inverno | 2.93 | 1.925
Estufa nascente 1 | 01 · Jardim de inverno | 2.93 | 1.925
Estufa nascente 2 | 01 · Jardim de inverno | 2.93 | 1.925
Estufa nascente 3 | 01 · Jardim de inverno | 2.93 | 1.925
Estufa nascente 4 | 01 · Jardim de inverno | 2.93 | 1.925
Caixa térmica 1 · west | 01 · Jardim de inverno | 2.15 | 4.7
Caixa térmica 1 · east | 01 · Jardim de inverno | 2.15 | 4.7
Caixa térmica 1 · south | 01 · Jardim de inverno | 2.15 | 0.9
Caixa térmica 2 · west | 01 · Jardim de inverno | 2.15 | 4.7
Caixa térmica 2 · east | 01 · Jardim de inverno | 2.15 | 4.7
Caixa térmica 2 · north | 01 · Jardim de inverno | 2.15 | 0.91
